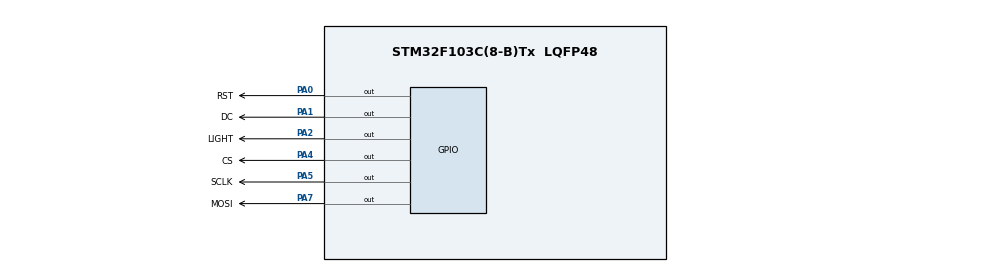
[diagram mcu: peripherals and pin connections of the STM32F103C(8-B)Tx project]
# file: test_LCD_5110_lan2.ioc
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Mcu.Family=STM32F1
Mcu.Name=STM32F103C(8-B)Tx
Mcu.Package=LQFP48
NVIC.PriorityGroup=NVIC_PRIORITYGROUP_4
PA0-WKUP.GPIO_Label=RST
PA0-WKUP.Signal=GPIO_Output
PA1.GPIO_Label=DC
PA1.Signal=GPIO_Output
PA13.Mode=Serial_Wire
PA13.Signal=SYS_JTMS-SWDIO
PA14.Mode=Serial_Wire
PA14.Signal=SYS_JTCK-SWCLK
PA2.GPIO_Label=LIGHT
PA2.Signal=GPIO_Output
PA4.GPIO_Label=CS
PA4.Signal=GPIO_Output
PA5.GPIO_Label=SCLK
PA5.Signal=GPIO_Output
PA7.GPIO_Label=MOSI
PA7.Signal=GPIO_Output
PD0-OSC_IN.Mode=HSE-External-Oscillator
PD0-OSC_IN.Signal=RCC_OSC_IN
PD1-OSC_OUT.Mode=HSE-External-Oscillator
PD1-OSC_OUT.Signal=RCC_OSC_OUT
ProjectManager.HeapSize=0x200
ProjectManager.StackSize=0x400
ProjectManager.TargetToolchain=STM32CubeIDE
RCC.AHBFreq_Value=72000000
RCC.APB1CLKDivider=RCC_HCLK_DIV2
RCC.APB1Freq_Value=36000000
RCC.APB1TimFreq_Value=72000000
RCC.APB2Freq_Value=72000000
RCC.APB2TimFreq_Value=72000000
RCC.HCLKFreq_Value=72000000
RCC.PLLMUL=RCC_PLL_MUL9
RCC.PLLSourceVirtual=RCC_PLLSOURCE_HSE
RCC.SYSCLKFreq_VALUE=72000000
RCC.SYSCLKSource=RCC_SYSCLKSOURCE_PLLCLK
RCC.USBFreq_Value=72000000
board=custom

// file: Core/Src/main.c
/* USER CODE BEGIN Header */
/* USER CODE END Header */

#include "main.h"
#include "5110.h"

void SystemClock_Config(void);
static void MX_GPIO_Init(void);
/* USER CODE BEGIN PFP */

void LCD5110_setup();
/* USER CODE END PFP */

int main(void)
{

  /* MCU Configuration--------------------------------------------------------*/

  /* Reset of all peripherals, Initializes the Flash interface and the Systick. */
  HAL_Init();

  /* Configure the system clock */
  SystemClock_Config();

  /* Initialize all configured peripherals */
  MX_GPIO_Init();
  /* USER CODE BEGIN 2 */
     unsigned char g = 0;
     const unsigned char txt1[11] = {"Wellcome To"};
     const unsigned char txt2[11] = {" Rang Dong "};
     signed char c = -9;
     char mode =1,cnt;
     signed int i = -66;
     float f = -0.04;
     LCD5110_setup();
     PCD8544_backlight_state(ON);
     HAL_Delay(2000);
     PCD8544_backlight_state(OFF);
     HAL_Delay(2000);
     PCD8544_clear_screen(WHITE);
     PCD8544_backlight_state(ON);
//     for(g = 0; g <= 10; g++)
//     {
//         PCD8544_set_cursor((13 + (g * 5)), 2);
//         PCD8544_print_char(txt1[g], WHITE);
//         HAL_Delay(150);
//     }
//
//     for(g = 0; g <= 10; g++)
//     {
//         PCD8544_set_cursor((13 + (g * 5)), 4);
//         PCD8544_print_char(txt2[g], WHITE);
//         HAL_Delay(150);
//     }
//        HAL_Delay(4000);

     PCD8544_clear_screen(WHITE);

  /* USER CODE END 2 */

  /* Infinite loop */
  /* USER CODE BEGIN WHILE */
  while(1)
  {
	        switch(mode)
	        {case 1: {
						PCD8544_print_string(1, 0, "    Hien Thi    ", BLACK);
						PCD8544_print_string(1, 2, " Nhiet Do:", WHITE);
						PCD8544_print_string(1, 3, " Do Am:", WHITE);
						PCD8544_print_string(1, 4, " Protect:", WHITE);
						print_chr(53, 2, c, WHITE);
						print_int(53, 3, i, WHITE);
						print_float(53, 4, f, 2, WHITE);
						c++;
						i++;
						f += 0.01;
						HAL_Delay(4000);
//						cnt=0;
//						cnt++; if(cnt>=10)
							mode =2;
						break;
	                 }
	         case 2: {
						PCD8544_print_string(1, 0, "    Cai Dat    ", BLACK);
						PCD8544_print_string(1, 2, " Nhiet Do:", WHITE);
						PCD8544_print_string(1, 3, " Do Am:", WHITE);
						PCD8544_print_string(1, 4, " Protect:", WHITE);
						print_chr(53, 2, c, WHITE);
						print_int(53, 3, i, WHITE);
						print_float(53, 4, f, 2, WHITE);
						c++;
						i++;
						f += 0.01;
						HAL_Delay(400);
						cnt=0;
						cnt++; if(cnt>=10)mode++;
						break;
	        	     }
	         default: mode=1;break;
	        }
    /* USER CODE END WHILE */
  }
}

void SystemClock_Config(void)
{
  RCC_OscInitTypeDef RCC_OscInitStruct = {0};
  RCC_ClkInitTypeDef RCC_ClkInitStruct = {0};

  /** Initializes the CPU, AHB and APB busses clocks
  */
  RCC_OscInitStruct.OscillatorType = RCC_OSCILLATORTYPE_HSE;
  RCC_OscInitStruct.HSEState = RCC_HSE_ON;
  RCC_OscInitStruct.HSEPredivValue = RCC_HSE_PREDIV_DIV1;
  RCC_OscInitStruct.HSIState = RCC_HSI_ON;
  RCC_OscInitStruct.PLL.PLLState = RCC_PLL_ON;
  RCC_OscInitStruct.PLL.PLLSource = RCC_PLLSOURCE_HSE;
  RCC_OscInitStruct.PLL.PLLMUL = RCC_PLL_MUL2;
  if (HAL_RCC_OscConfig(&RCC_OscInitStruct) != HAL_OK)
  {
    Error_Handler();
  }
  /** Initializes the CPU, AHB and APB busses clocks
  */
  RCC_ClkInitStruct.ClockType = RCC_CLOCKTYPE_HCLK|RCC_CLOCKTYPE_SYSCLK
                              |RCC_CLOCKTYPE_PCLK1|RCC_CLOCKTYPE_PCLK2;
  RCC_ClkInitStruct.SYSCLKSource = RCC_SYSCLKSOURCE_PLLCLK;
  RCC_ClkInitStruct.AHBCLKDivider = RCC_SYSCLK_DIV2;
  RCC_ClkInitStruct.APB1CLKDivider = RCC_HCLK_DIV2;
  RCC_ClkInitStruct.APB2CLKDivider = RCC_HCLK_DIV1;

  if (HAL_RCC_ClockConfig(&RCC_ClkInitStruct, FLASH_LATENCY_0) != HAL_OK)
  {
    Error_Handler();
  }
}

static void MX_GPIO_Init(void)
{
  GPIO_InitTypeDef GPIO_InitStruct = {0};

  /* GPIO Ports Clock Enable */
  __HAL_RCC_GPIOD_CLK_ENABLE();
  __HAL_RCC_GPIOA_CLK_ENABLE();

  /*Configure GPIO pin Output Level */
  HAL_GPIO_WritePin(GPIOA, RST_Pin|DC_Pin|LIGHT_Pin|CS_Pin
                          |SCLK_Pin|MOSI_Pin, GPIO_PIN_RESET);

  /*Configure GPIO pins : RST_Pin DC_Pin LIGHT_Pin CS_Pin
                           SCLK_Pin MOSI_Pin */
  GPIO_InitStruct.Pin = RST_Pin|DC_Pin|LIGHT_Pin|CS_Pin
                          |SCLK_Pin|MOSI_Pin;
  GPIO_InitStruct.Mode = GPIO_MODE_OUTPUT_PP;
  GPIO_InitStruct.Pull = GPIO_NOPULL;
  GPIO_InitStruct.Speed = GPIO_SPEED_FREQ_HIGH;
  HAL_GPIO_Init(GPIOA, &GPIO_InitStruct);

}

/* USER CODE BEGIN 4 */

void LCD5110_setup()
{
    PCD8544_init();
    PCD8544_clear_screen(WHITE);
}
/* USER CODE END 4 */

void Error_Handler(void)
{
}

/************************ (C) COPYRIGHT STMicroelectronics *****END OF FILE****/
